VERSION 5.7 ;
  NOWIREEXTENSIONATPIN ON ;
  DIVIDERCHAR "/" ;
  BUSBITCHARS "[]" ;
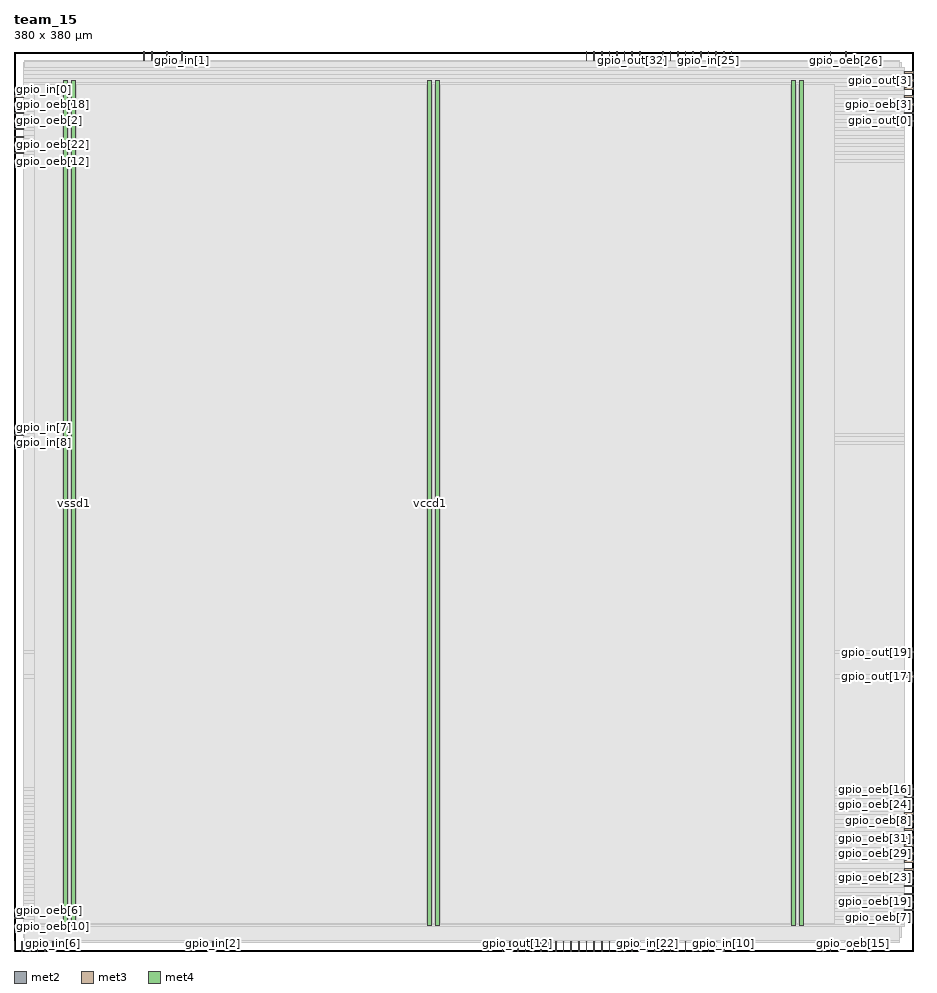
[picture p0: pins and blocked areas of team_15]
MACRO team_15
  CLASS BLOCK ;
  FOREIGN team_15 ;
  ORIGIN 0.000 0.000 ;
  SIZE 380.000 BY 380.000 ;
  PIN clk
    DIRECTION INPUT ;
    USE SIGNAL ;
    PORT
      LAYER met2 ;
        RECT 0.090 0.000 0.370 4.000 ;
    END
  END clk
  PIN en
    DIRECTION INPUT ;
    USE SIGNAL ;
    PORT
      LAYER met2 ;
        RECT 3.310 0.000 3.590 4.000 ;
    END
  END en
  PIN gpio_in[0]
    DIRECTION INPUT ;
    USE SIGNAL ;
    ANTENNAGATEAREA 0.647700 ;
    ANTENNADIFFAREA 0.434700 ;
    PORT
      LAYER met3 ;
        RECT 0.000 360.440 4.000 361.040 ;
    END
  END gpio_in[0]
  PIN gpio_in[10]
    DIRECTION INPUT ;
    USE SIGNAL ;
    ANTENNAGATEAREA 0.647700 ;
    ANTENNADIFFAREA 0.434700 ;
    PORT
      LAYER met2 ;
        RECT 299.550 0.000 299.830 4.000 ;
    END
  END gpio_in[10]
  PIN gpio_in[11]
    DIRECTION INPUT ;
    USE SIGNAL ;
    ANTENNAGATEAREA 0.593700 ;
    ANTENNADIFFAREA 0.434700 ;
    PORT
      LAYER met2 ;
        RECT 296.330 0.000 296.610 4.000 ;
    END
  END gpio_in[11]
  PIN gpio_in[12]
    DIRECTION INPUT ;
    USE SIGNAL ;
    ANTENNAGATEAREA 0.593700 ;
    ANTENNADIFFAREA 0.434700 ;
    PORT
      LAYER met2 ;
        RECT 289.890 0.000 290.170 4.000 ;
    END
  END gpio_in[12]
  PIN gpio_in[13]
    DIRECTION INPUT ;
    USE SIGNAL ;
    ANTENNAGATEAREA 0.647700 ;
    ANTENNADIFFAREA 0.434700 ;
    PORT
      LAYER met2 ;
        RECT 283.450 0.000 283.730 4.000 ;
    END
  END gpio_in[13]
  PIN gpio_in[14]
    DIRECTION INPUT ;
    USE SIGNAL ;
    ANTENNAGATEAREA 0.647700 ;
    ANTENNADIFFAREA 0.434700 ;
    PORT
      LAYER met2 ;
        RECT 286.670 0.000 286.950 4.000 ;
    END
  END gpio_in[14]
  PIN gpio_in[15]
    DIRECTION INPUT ;
    USE SIGNAL ;
    ANTENNAGATEAREA 0.593700 ;
    ANTENNADIFFAREA 0.434700 ;
    PORT
      LAYER met2 ;
        RECT 293.110 0.000 293.390 4.000 ;
    END
  END gpio_in[15]
  PIN gpio_in[16]
    DIRECTION INPUT ;
    USE SIGNAL ;
    ANTENNAGATEAREA 0.593700 ;
    ANTENNADIFFAREA 0.434700 ;
    PORT
      LAYER met2 ;
        RECT 280.230 0.000 280.510 4.000 ;
    END
  END gpio_in[16]
  PIN gpio_in[17]
    DIRECTION INPUT ;
    USE SIGNAL ;
    ANTENNAGATEAREA 0.647700 ;
    ANTENNADIFFAREA 0.434700 ;
    PORT
      LAYER met2 ;
        RECT 273.790 0.000 274.070 4.000 ;
    END
  END gpio_in[17]
  PIN gpio_in[18]
    DIRECTION INPUT ;
    USE SIGNAL ;
    ANTENNAGATEAREA 0.647700 ;
    ANTENNADIFFAREA 0.434700 ;
    PORT
      LAYER met2 ;
        RECT 264.130 0.000 264.410 4.000 ;
    END
  END gpio_in[18]
  PIN gpio_in[19]
    DIRECTION INPUT ;
    USE SIGNAL ;
    ANTENNAGATEAREA 0.647700 ;
    ANTENNADIFFAREA 0.434700 ;
    PORT
      LAYER met2 ;
        RECT 257.690 0.000 257.970 4.000 ;
    END
  END gpio_in[19]
  PIN gpio_in[1]
    DIRECTION INPUT ;
    USE SIGNAL ;
    ANTENNAGATEAREA 0.631200 ;
    ANTENNADIFFAREA 0.434700 ;
    PORT
      LAYER met2 ;
        RECT 70.930 376.000 71.210 380.000 ;
    END
  END gpio_in[1]
  PIN gpio_in[20]
    DIRECTION INPUT ;
    USE SIGNAL ;
    ANTENNAGATEAREA 0.647700 ;
    ANTENNADIFFAREA 0.434700 ;
    PORT
      LAYER met2 ;
        RECT 244.810 0.000 245.090 4.000 ;
    END
  END gpio_in[20]
  PIN gpio_in[21]
    DIRECTION INPUT ;
    USE SIGNAL ;
    ANTENNAGATEAREA 0.647700 ;
    ANTENNADIFFAREA 0.434700 ;
    PORT
      LAYER met2 ;
        RECT 270.570 0.000 270.850 4.000 ;
    END
  END gpio_in[21]
  PIN gpio_in[22]
    DIRECTION INPUT ;
    USE SIGNAL ;
    ANTENNAGATEAREA 0.647700 ;
    ANTENNADIFFAREA 0.434700 ;
    PORT
      LAYER met2 ;
        RECT 267.350 0.000 267.630 4.000 ;
    END
  END gpio_in[22]
  PIN gpio_in[23]
    DIRECTION INPUT ;
    USE SIGNAL ;
    ANTENNAGATEAREA 0.593700 ;
    ANTENNADIFFAREA 0.434700 ;
    PORT
      LAYER met2 ;
        RECT 251.250 0.000 251.530 4.000 ;
    END
  END gpio_in[23]
  PIN gpio_in[24]
    DIRECTION INPUT ;
    USE SIGNAL ;
    ANTENNAGATEAREA 0.647700 ;
    ANTENNADIFFAREA 0.434700 ;
    PORT
      LAYER met2 ;
        RECT 260.910 0.000 261.190 4.000 ;
    END
  END gpio_in[24]
  PIN gpio_in[25]
    DIRECTION INPUT ;
    USE SIGNAL ;
    ANTENNAGATEAREA 0.593700 ;
    ANTENNADIFFAREA 0.434700 ;
    PORT
      LAYER met2 ;
        RECT 293.110 376.000 293.390 380.000 ;
    END
  END gpio_in[25]
  PIN gpio_in[26]
    DIRECTION INPUT ;
    USE SIGNAL ;
    ANTENNAGATEAREA 0.593700 ;
    ANTENNADIFFAREA 0.434700 ;
    PORT
      LAYER met2 ;
        RECT 302.770 376.000 303.050 380.000 ;
    END
  END gpio_in[26]
  PIN gpio_in[27]
    DIRECTION INPUT ;
    USE SIGNAL ;
    ANTENNAGATEAREA 0.593700 ;
    ANTENNADIFFAREA 0.434700 ;
    PORT
      LAYER met2 ;
        RECT 296.330 376.000 296.610 380.000 ;
    END
  END gpio_in[27]
  PIN gpio_in[28]
    DIRECTION INPUT ;
    USE SIGNAL ;
    ANTENNAGATEAREA 0.593700 ;
    ANTENNADIFFAREA 0.434700 ;
    PORT
      LAYER met2 ;
        RECT 283.450 376.000 283.730 380.000 ;
    END
  END gpio_in[28]
  PIN gpio_in[29]
    DIRECTION INPUT ;
    USE SIGNAL ;
    ANTENNAGATEAREA 0.593700 ;
    ANTENNADIFFAREA 0.434700 ;
    PORT
      LAYER met2 ;
        RECT 289.890 376.000 290.170 380.000 ;
    END
  END gpio_in[29]
  PIN gpio_in[2]
    DIRECTION INPUT ;
    USE SIGNAL ;
    ANTENNAGATEAREA 0.631200 ;
    ANTENNADIFFAREA 0.434700 ;
    PORT
      LAYER met2 ;
        RECT 83.810 0.000 84.090 4.000 ;
    END
  END gpio_in[2]
  PIN gpio_in[30]
    DIRECTION INPUT ;
    USE SIGNAL ;
    ANTENNAGATEAREA 0.593700 ;
    ANTENNADIFFAREA 0.434700 ;
    PORT
      LAYER met2 ;
        RECT 286.670 376.000 286.950 380.000 ;
    END
  END gpio_in[30]
  PIN gpio_in[31]
    DIRECTION INPUT ;
    USE SIGNAL ;
    ANTENNAGATEAREA 0.593700 ;
    ANTENNADIFFAREA 0.434700 ;
    PORT
      LAYER met2 ;
        RECT 273.790 376.000 274.070 380.000 ;
    END
  END gpio_in[31]
  PIN gpio_in[32]
    DIRECTION INPUT ;
    USE SIGNAL ;
    ANTENNAGATEAREA 0.593700 ;
    ANTENNADIFFAREA 0.434700 ;
    PORT
      LAYER met2 ;
        RECT 280.230 376.000 280.510 380.000 ;
    END
  END gpio_in[32]
  PIN gpio_in[33]
    DIRECTION INPUT ;
    USE SIGNAL ;
    ANTENNAGATEAREA 0.647700 ;
    ANTENNADIFFAREA 0.434700 ;
    PORT
      LAYER met2 ;
        RECT 299.550 376.000 299.830 380.000 ;
    END
  END gpio_in[33]
  PIN gpio_in[3]
    DIRECTION INPUT ;
    USE SIGNAL ;
    PORT
      LAYER met2 ;
        RECT 6.530 0.000 6.810 4.000 ;
    END
  END gpio_in[3]
  PIN gpio_in[4]
    DIRECTION INPUT ;
    USE SIGNAL ;
    PORT
      LAYER met2 ;
        RECT 9.750 0.000 10.030 4.000 ;
    END
  END gpio_in[4]
  PIN gpio_in[5]
    DIRECTION INPUT ;
    USE SIGNAL ;
    PORT
      LAYER met2 ;
        RECT 12.970 0.000 13.250 4.000 ;
    END
  END gpio_in[5]
  PIN gpio_in[6]
    DIRECTION INPUT ;
    USE SIGNAL ;
    PORT
      LAYER met2 ;
        RECT 16.190 0.000 16.470 4.000 ;
    END
  END gpio_in[6]
  PIN gpio_in[7]
    DIRECTION INPUT ;
    USE SIGNAL ;
    ANTENNAGATEAREA 0.593700 ;
    ANTENNADIFFAREA 0.434700 ;
    PORT
      LAYER met3 ;
        RECT 0.000 217.640 4.000 218.240 ;
    END
  END gpio_in[7]
  PIN gpio_in[8]
    DIRECTION INPUT ;
    USE SIGNAL ;
    ANTENNAGATEAREA 0.682200 ;
    ANTENNADIFFAREA 0.434700 ;
    PORT
      LAYER met3 ;
        RECT 0.000 214.240 4.000 214.840 ;
    END
  END gpio_in[8]
  PIN gpio_in[9]
    DIRECTION INPUT ;
    USE SIGNAL ;
    ANTENNAGATEAREA 0.647700 ;
    ANTENNADIFFAREA 0.434700 ;
    PORT
      LAYER met2 ;
        RECT 277.010 0.000 277.290 4.000 ;
    END
  END gpio_in[9]
  PIN gpio_oeb[0]
    DIRECTION OUTPUT ;
    USE SIGNAL ;
    PORT
      LAYER met3 ;
        RECT 376.000 370.640 380.000 371.240 ;
    END
  END gpio_oeb[0]
  PIN gpio_oeb[10]
    DIRECTION OUTPUT ;
    USE SIGNAL ;
    PORT
      LAYER met3 ;
        RECT 0.000 10.240 4.000 10.840 ;
    END
  END gpio_oeb[10]
  PIN gpio_oeb[11]
    DIRECTION OUTPUT ;
    USE SIGNAL ;
    ANTENNADIFFAREA 0.445500 ;
    PORT
      LAYER met2 ;
        RECT 344.630 0.000 344.910 4.000 ;
    END
  END gpio_oeb[11]
  PIN gpio_oeb[12]
    DIRECTION OUTPUT ;
    USE SIGNAL ;
    PORT
      LAYER met3 ;
        RECT 0.000 333.240 4.000 333.840 ;
    END
  END gpio_oeb[12]
  PIN gpio_oeb[13]
    DIRECTION OUTPUT ;
    USE SIGNAL ;
    ANTENNADIFFAREA 0.445500 ;
    PORT
      LAYER met2 ;
        RECT 351.070 0.000 351.350 4.000 ;
    END
  END gpio_oeb[13]
  PIN gpio_oeb[14]
    DIRECTION OUTPUT ;
    USE SIGNAL ;
    PORT
      LAYER met3 ;
        RECT 376.000 54.440 380.000 55.040 ;
    END
  END gpio_oeb[14]
  PIN gpio_oeb[15]
    DIRECTION OUTPUT ;
    USE SIGNAL ;
    ANTENNADIFFAREA 0.445500 ;
    PORT
      LAYER met2 ;
        RECT 354.290 0.000 354.570 4.000 ;
    END
  END gpio_oeb[15]
  PIN gpio_oeb[16]
    DIRECTION OUTPUT ;
    USE SIGNAL ;
    PORT
      LAYER met3 ;
        RECT 376.000 68.040 380.000 68.640 ;
    END
  END gpio_oeb[16]
  PIN gpio_oeb[17]
    DIRECTION OUTPUT ;
    USE SIGNAL ;
    ANTENNADIFFAREA 0.445500 ;
    PORT
      LAYER met2 ;
        RECT 360.730 0.000 361.010 4.000 ;
    END
  END gpio_oeb[17]
  PIN gpio_oeb[18]
    DIRECTION OUTPUT ;
    USE SIGNAL ;
    PORT
      LAYER met3 ;
        RECT 0.000 357.040 4.000 357.640 ;
    END
  END gpio_oeb[18]
  PIN gpio_oeb[19]
    DIRECTION OUTPUT ;
    USE SIGNAL ;
    ANTENNADIFFAREA 0.445500 ;
    PORT
      LAYER met3 ;
        RECT 376.000 20.440 380.000 21.040 ;
    END
  END gpio_oeb[19]
  PIN gpio_oeb[1]
    DIRECTION OUTPUT ;
    USE SIGNAL ;
    PORT
      LAYER met3 ;
        RECT 0.000 353.640 4.000 354.240 ;
    END
  END gpio_oeb[1]
  PIN gpio_oeb[20]
    DIRECTION OUTPUT ;
    USE SIGNAL ;
    PORT
      LAYER met3 ;
        RECT 0.000 346.840 4.000 347.440 ;
    END
  END gpio_oeb[20]
  PIN gpio_oeb[21]
    DIRECTION OUTPUT ;
    USE SIGNAL ;
    ANTENNADIFFAREA 0.445500 ;
    PORT
      LAYER met3 ;
        RECT 376.000 23.840 380.000 24.440 ;
    END
  END gpio_oeb[21]
  PIN gpio_oeb[22]
    DIRECTION OUTPUT ;
    USE SIGNAL ;
    PORT
      LAYER met3 ;
        RECT 0.000 340.040 4.000 340.640 ;
    END
  END gpio_oeb[22]
  PIN gpio_oeb[23]
    DIRECTION OUTPUT ;
    USE SIGNAL ;
    ANTENNADIFFAREA 0.445500 ;
    PORT
      LAYER met3 ;
        RECT 376.000 30.640 380.000 31.240 ;
    END
  END gpio_oeb[23]
  PIN gpio_oeb[24]
    DIRECTION OUTPUT ;
    USE SIGNAL ;
    PORT
      LAYER met3 ;
        RECT 376.000 64.640 380.000 65.240 ;
    END
  END gpio_oeb[24]
  PIN gpio_oeb[25]
    DIRECTION OUTPUT ;
    USE SIGNAL ;
    ANTENNADIFFAREA 0.445500 ;
    PORT
      LAYER met3 ;
        RECT 376.000 34.040 380.000 34.640 ;
    END
  END gpio_oeb[25]
  PIN gpio_oeb[26]
    DIRECTION OUTPUT ;
    USE SIGNAL ;
    PORT
      LAYER met2 ;
        RECT 351.070 376.000 351.350 380.000 ;
    END
  END gpio_oeb[26]
  PIN gpio_oeb[27]
    DIRECTION OUTPUT ;
    USE SIGNAL ;
    ANTENNADIFFAREA 0.445500 ;
    PORT
      LAYER met3 ;
        RECT 376.000 37.440 380.000 38.040 ;
    END
  END gpio_oeb[27]
  PIN gpio_oeb[28]
    DIRECTION OUTPUT ;
    USE SIGNAL ;
    PORT
      LAYER met3 ;
        RECT 376.000 360.440 380.000 361.040 ;
    END
  END gpio_oeb[28]
  PIN gpio_oeb[29]
    DIRECTION OUTPUT ;
    USE SIGNAL ;
    ANTENNADIFFAREA 0.445500 ;
    PORT
      LAYER met3 ;
        RECT 376.000 40.840 380.000 41.440 ;
    END
  END gpio_oeb[29]
  PIN gpio_oeb[2]
    DIRECTION OUTPUT ;
    USE SIGNAL ;
    PORT
      LAYER met3 ;
        RECT 0.000 350.240 4.000 350.840 ;
    END
  END gpio_oeb[2]
  PIN gpio_oeb[30]
    DIRECTION OUTPUT ;
    USE SIGNAL ;
    PORT
      LAYER met3 ;
        RECT 376.000 27.240 380.000 27.840 ;
    END
  END gpio_oeb[30]
  PIN gpio_oeb[31]
    DIRECTION OUTPUT ;
    USE SIGNAL ;
    ANTENNADIFFAREA 0.445500 ;
    PORT
      LAYER met3 ;
        RECT 376.000 44.240 380.000 44.840 ;
    END
  END gpio_oeb[31]
  PIN gpio_oeb[32]
    DIRECTION OUTPUT ;
    USE SIGNAL ;
    PORT
      LAYER met3 ;
        RECT 0.000 17.040 4.000 17.640 ;
    END
  END gpio_oeb[32]
  PIN gpio_oeb[33]
    DIRECTION OUTPUT ;
    USE SIGNAL ;
    ANTENNADIFFAREA 0.445500 ;
    PORT
      LAYER met3 ;
        RECT 376.000 47.640 380.000 48.240 ;
    END
  END gpio_oeb[33]
  PIN gpio_oeb[3]
    DIRECTION OUTPUT ;
    USE SIGNAL ;
    PORT
      LAYER met3 ;
        RECT 376.000 357.040 380.000 357.640 ;
    END
  END gpio_oeb[3]
  PIN gpio_oeb[4]
    DIRECTION OUTPUT ;
    USE SIGNAL ;
    PORT
      LAYER met3 ;
        RECT 0.000 343.440 4.000 344.040 ;
    END
  END gpio_oeb[4]
  PIN gpio_oeb[5]
    DIRECTION OUTPUT ;
    USE SIGNAL ;
    PORT
      LAYER met3 ;
        RECT 376.000 353.640 380.000 354.240 ;
    END
  END gpio_oeb[5]
  PIN gpio_oeb[6]
    DIRECTION OUTPUT ;
    USE SIGNAL ;
    PORT
      LAYER met3 ;
        RECT 0.000 13.640 4.000 14.240 ;
    END
  END gpio_oeb[6]
  PIN gpio_oeb[7]
    DIRECTION OUTPUT ;
    USE SIGNAL ;
    PORT
      LAYER met3 ;
        RECT 376.000 17.040 380.000 17.640 ;
    END
  END gpio_oeb[7]
  PIN gpio_oeb[8]
    DIRECTION OUTPUT ;
    USE SIGNAL ;
    PORT
      LAYER met3 ;
        RECT 376.000 57.840 380.000 58.440 ;
    END
  END gpio_oeb[8]
  PIN gpio_oeb[9]
    DIRECTION OUTPUT ;
    USE SIGNAL ;
    ANTENNADIFFAREA 0.445500 ;
    PORT
      LAYER met2 ;
        RECT 341.410 0.000 341.690 4.000 ;
    END
  END gpio_oeb[9]
  PIN gpio_out[0]
    DIRECTION OUTPUT ;
    USE SIGNAL ;
    PORT
      LAYER met3 ;
        RECT 376.000 350.240 380.000 350.840 ;
    END
  END gpio_out[0]
  PIN gpio_out[10]
    DIRECTION OUTPUT ;
    USE SIGNAL ;
    ANTENNADIFFAREA 0.445500 ;
    PORT
      LAYER met2 ;
        RECT 206.170 0.000 206.450 4.000 ;
    END
  END gpio_out[10]
  PIN gpio_out[11]
    DIRECTION OUTPUT ;
    USE SIGNAL ;
    ANTENNADIFFAREA 0.445500 ;
    PORT
      LAYER met2 ;
        RECT 209.390 0.000 209.670 4.000 ;
    END
  END gpio_out[11]
  PIN gpio_out[12]
    DIRECTION OUTPUT ;
    USE SIGNAL ;
    ANTENNADIFFAREA 0.445500 ;
    PORT
      LAYER met2 ;
        RECT 212.610 0.000 212.890 4.000 ;
    END
  END gpio_out[12]
  PIN gpio_out[13]
    DIRECTION OUTPUT ;
    USE SIGNAL ;
    ANTENNADIFFAREA 0.445500 ;
    PORT
      LAYER met2 ;
        RECT 228.710 0.000 228.990 4.000 ;
    END
  END gpio_out[13]
  PIN gpio_out[14]
    DIRECTION OUTPUT ;
    USE SIGNAL ;
    ANTENNADIFFAREA 0.445500 ;
    PORT
      LAYER met2 ;
        RECT 225.490 0.000 225.770 4.000 ;
    END
  END gpio_out[14]
  PIN gpio_out[15]
    DIRECTION OUTPUT ;
    USE SIGNAL ;
    ANTENNADIFFAREA 0.445500 ;
    PORT
      LAYER met2 ;
        RECT 219.050 0.000 219.330 4.000 ;
    END
  END gpio_out[15]
  PIN gpio_out[16]
    DIRECTION OUTPUT ;
    USE SIGNAL ;
    ANTENNADIFFAREA 0.445500 ;
    PORT
      LAYER met2 ;
        RECT 215.830 0.000 216.110 4.000 ;
    END
  END gpio_out[16]
  PIN gpio_out[17]
    DIRECTION OUTPUT ;
    USE SIGNAL ;
    ANTENNADIFFAREA 0.445500 ;
    PORT
      LAYER met3 ;
        RECT 376.000 115.640 380.000 116.240 ;
    END
  END gpio_out[17]
  PIN gpio_out[18]
    DIRECTION OUTPUT ;
    USE SIGNAL ;
    ANTENNADIFFAREA 0.445500 ;
    PORT
      LAYER met2 ;
        RECT 254.470 0.000 254.750 4.000 ;
    END
  END gpio_out[18]
  PIN gpio_out[19]
    DIRECTION OUTPUT ;
    USE SIGNAL ;
    ANTENNADIFFAREA 0.445500 ;
    PORT
      LAYER met3 ;
        RECT 376.000 125.840 380.000 126.440 ;
    END
  END gpio_out[19]
  PIN gpio_out[1]
    DIRECTION OUTPUT ;
    USE SIGNAL ;
    PORT
      LAYER met3 ;
        RECT 0.000 336.640 4.000 337.240 ;
    END
  END gpio_out[1]
  PIN gpio_out[20]
    DIRECTION OUTPUT ;
    USE SIGNAL ;
    ANTENNADIFFAREA 0.445500 ;
    PORT
      LAYER met2 ;
        RECT 222.270 0.000 222.550 4.000 ;
    END
  END gpio_out[20]
  PIN gpio_out[21]
    DIRECTION OUTPUT ;
    USE SIGNAL ;
    ANTENNADIFFAREA 0.445500 ;
    PORT
      LAYER met2 ;
        RECT 235.150 0.000 235.430 4.000 ;
    END
  END gpio_out[21]
  PIN gpio_out[22]
    DIRECTION OUTPUT ;
    USE SIGNAL ;
    ANTENNADIFFAREA 0.445500 ;
    PORT
      LAYER met2 ;
        RECT 238.370 0.000 238.650 4.000 ;
    END
  END gpio_out[22]
  PIN gpio_out[23]
    DIRECTION OUTPUT ;
    USE SIGNAL ;
    ANTENNADIFFAREA 0.445500 ;
    PORT
      LAYER met2 ;
        RECT 231.930 0.000 232.210 4.000 ;
    END
  END gpio_out[23]
  PIN gpio_out[24]
    DIRECTION OUTPUT ;
    USE SIGNAL ;
    ANTENNADIFFAREA 0.445500 ;
    PORT
      LAYER met2 ;
        RECT 241.590 0.000 241.870 4.000 ;
    END
  END gpio_out[24]
  PIN gpio_out[25]
    DIRECTION OUTPUT ;
    USE SIGNAL ;
    ANTENNADIFFAREA 0.445500 ;
    PORT
      LAYER met2 ;
        RECT 264.130 376.000 264.410 380.000 ;
    END
  END gpio_out[25]
  PIN gpio_out[26]
    DIRECTION OUTPUT ;
    USE SIGNAL ;
    ANTENNADIFFAREA 0.445500 ;
    PORT
      LAYER met2 ;
        RECT 254.470 376.000 254.750 380.000 ;
    END
  END gpio_out[26]
  PIN gpio_out[27]
    DIRECTION OUTPUT ;
    USE SIGNAL ;
    ANTENNADIFFAREA 0.445500 ;
    PORT
      LAYER met2 ;
        RECT 244.810 376.000 245.090 380.000 ;
    END
  END gpio_out[27]
  PIN gpio_out[28]
    DIRECTION OUTPUT ;
    USE SIGNAL ;
    ANTENNADIFFAREA 0.445500 ;
    PORT
      LAYER met2 ;
        RECT 257.690 376.000 257.970 380.000 ;
    END
  END gpio_out[28]
  PIN gpio_out[29]
    DIRECTION OUTPUT ;
    USE SIGNAL ;
    ANTENNADIFFAREA 0.445500 ;
    PORT
      LAYER met2 ;
        RECT 248.030 376.000 248.310 380.000 ;
    END
  END gpio_out[29]
  PIN gpio_out[2]
    DIRECTION OUTPUT ;
    USE SIGNAL ;
    PORT
      LAYER met3 ;
        RECT 376.000 61.240 380.000 61.840 ;
    END
  END gpio_out[2]
  PIN gpio_out[30]
    DIRECTION OUTPUT ;
    USE SIGNAL ;
    ANTENNADIFFAREA 0.445500 ;
    PORT
      LAYER met2 ;
        RECT 251.250 376.000 251.530 380.000 ;
    END
  END gpio_out[30]
  PIN gpio_out[31]
    DIRECTION OUTPUT ;
    USE SIGNAL ;
    ANTENNADIFFAREA 0.445500 ;
    PORT
      LAYER met2 ;
        RECT 241.590 376.000 241.870 380.000 ;
    END
  END gpio_out[31]
  PIN gpio_out[32]
    DIRECTION OUTPUT ;
    USE SIGNAL ;
    ANTENNADIFFAREA 0.445500 ;
    PORT
      LAYER met2 ;
        RECT 260.910 376.000 261.190 380.000 ;
    END
  END gpio_out[32]
  PIN gpio_out[33]
    DIRECTION OUTPUT ;
    USE SIGNAL ;
    ANTENNADIFFAREA 0.445500 ;
    PORT
      LAYER met2 ;
        RECT 277.010 376.000 277.290 380.000 ;
    END
  END gpio_out[33]
  PIN gpio_out[3]
    DIRECTION OUTPUT ;
    USE SIGNAL ;
    PORT
      LAYER met3 ;
        RECT 376.000 367.240 380.000 367.840 ;
    END
  END gpio_out[3]
  PIN gpio_out[4]
    DIRECTION OUTPUT ;
    USE SIGNAL ;
    ANTENNADIFFAREA 0.445500 ;
    PORT
      LAYER met2 ;
        RECT 64.490 376.000 64.770 380.000 ;
    END
  END gpio_out[4]
  PIN gpio_out[5]
    DIRECTION OUTPUT ;
    USE SIGNAL ;
    ANTENNADIFFAREA 0.445500 ;
    PORT
      LAYER met2 ;
        RECT 58.050 376.000 58.330 380.000 ;
    END
  END gpio_out[5]
  PIN gpio_out[6]
    DIRECTION OUTPUT ;
    USE SIGNAL ;
    ANTENNADIFFAREA 0.445500 ;
    PORT
      LAYER met2 ;
        RECT 54.830 376.000 55.110 380.000 ;
    END
  END gpio_out[6]
  PIN gpio_out[7]
    DIRECTION OUTPUT ;
    USE SIGNAL ;
    PORT
      LAYER met2 ;
        RECT 344.630 376.000 344.910 380.000 ;
    END
  END gpio_out[7]
  PIN gpio_out[8]
    DIRECTION OUTPUT ;
    USE SIGNAL ;
    PORT
      LAYER met3 ;
        RECT 376.000 363.840 380.000 364.440 ;
    END
  END gpio_out[8]
  PIN gpio_out[9]
    DIRECTION OUTPUT ;
    USE SIGNAL ;
    ANTENNADIFFAREA 0.445500 ;
    PORT
      LAYER met2 ;
        RECT 248.030 0.000 248.310 4.000 ;
    END
  END gpio_out[9]
  PIN nrst
    DIRECTION INPUT ;
    USE SIGNAL ;
    ANTENNAGATEAREA 0.647700 ;
    ANTENNADIFFAREA 0.434700 ;
    PORT
      LAYER met3 ;
        RECT 376.000 51.040 380.000 51.640 ;
    END
  END nrst
  PIN vccd1
    DIRECTION INOUT ;
    USE POWER ;
    PORT
      LAYER met4 ;
        RECT 21.040 10.640 22.640 367.440 ;
    END
    PORT
      LAYER met4 ;
        RECT 174.640 10.640 176.240 367.440 ;
    END
    PORT
      LAYER met4 ;
        RECT 328.240 10.640 329.840 367.440 ;
    END
  END vccd1
  PIN vssd1
    DIRECTION INOUT ;
    USE GROUND ;
    PORT
      LAYER met4 ;
        RECT 24.340 10.640 25.940 367.440 ;
    END
    PORT
      LAYER met4 ;
        RECT 177.940 10.640 179.540 367.440 ;
    END
    PORT
      LAYER met4 ;
        RECT 331.540 10.640 333.140 367.440 ;
    END
  END vssd1
  OBS
      LAYER nwell ;
        RECT 5.330 10.760 374.630 367.390 ;
      LAYER li1 ;
        RECT 5.520 10.795 374.440 367.285 ;
      LAYER met1 ;
        RECT 4.210 5.820 374.740 374.980 ;
      LAYER met2 ;
        RECT 4.230 375.720 54.550 376.000 ;
        RECT 55.390 375.720 57.770 376.000 ;
        RECT 58.610 375.720 64.210 376.000 ;
        RECT 65.050 375.720 70.650 376.000 ;
        RECT 71.490 375.720 241.310 376.000 ;
        RECT 242.150 375.720 244.530 376.000 ;
        RECT 245.370 375.720 247.750 376.000 ;
        RECT 248.590 375.720 250.970 376.000 ;
        RECT 251.810 375.720 254.190 376.000 ;
        RECT 255.030 375.720 257.410 376.000 ;
        RECT 258.250 375.720 260.630 376.000 ;
        RECT 261.470 375.720 263.850 376.000 ;
        RECT 264.690 375.720 273.510 376.000 ;
        RECT 274.350 375.720 276.730 376.000 ;
        RECT 277.570 375.720 279.950 376.000 ;
        RECT 280.790 375.720 283.170 376.000 ;
        RECT 284.010 375.720 286.390 376.000 ;
        RECT 287.230 375.720 289.610 376.000 ;
        RECT 290.450 375.720 292.830 376.000 ;
        RECT 293.670 375.720 296.050 376.000 ;
        RECT 296.890 375.720 299.270 376.000 ;
        RECT 300.110 375.720 302.490 376.000 ;
        RECT 303.330 375.720 344.350 376.000 ;
        RECT 345.190 375.720 350.790 376.000 ;
        RECT 351.630 375.720 373.890 376.000 ;
        RECT 4.230 4.280 373.890 375.720 ;
        RECT 4.230 3.670 6.250 4.280 ;
        RECT 7.090 3.670 9.470 4.280 ;
        RECT 10.310 3.670 12.690 4.280 ;
        RECT 13.530 3.670 15.910 4.280 ;
        RECT 16.750 3.670 83.530 4.280 ;
        RECT 84.370 3.670 205.890 4.280 ;
        RECT 206.730 3.670 209.110 4.280 ;
        RECT 209.950 3.670 212.330 4.280 ;
        RECT 213.170 3.670 215.550 4.280 ;
        RECT 216.390 3.670 218.770 4.280 ;
        RECT 219.610 3.670 221.990 4.280 ;
        RECT 222.830 3.670 225.210 4.280 ;
        RECT 226.050 3.670 228.430 4.280 ;
        RECT 229.270 3.670 231.650 4.280 ;
        RECT 232.490 3.670 234.870 4.280 ;
        RECT 235.710 3.670 238.090 4.280 ;
        RECT 238.930 3.670 241.310 4.280 ;
        RECT 242.150 3.670 244.530 4.280 ;
        RECT 245.370 3.670 247.750 4.280 ;
        RECT 248.590 3.670 250.970 4.280 ;
        RECT 251.810 3.670 254.190 4.280 ;
        RECT 255.030 3.670 257.410 4.280 ;
        RECT 258.250 3.670 260.630 4.280 ;
        RECT 261.470 3.670 263.850 4.280 ;
        RECT 264.690 3.670 267.070 4.280 ;
        RECT 267.910 3.670 270.290 4.280 ;
        RECT 271.130 3.670 273.510 4.280 ;
        RECT 274.350 3.670 276.730 4.280 ;
        RECT 277.570 3.670 279.950 4.280 ;
        RECT 280.790 3.670 283.170 4.280 ;
        RECT 284.010 3.670 286.390 4.280 ;
        RECT 287.230 3.670 289.610 4.280 ;
        RECT 290.450 3.670 292.830 4.280 ;
        RECT 293.670 3.670 296.050 4.280 ;
        RECT 296.890 3.670 299.270 4.280 ;
        RECT 300.110 3.670 341.130 4.280 ;
        RECT 341.970 3.670 344.350 4.280 ;
        RECT 345.190 3.670 350.790 4.280 ;
        RECT 351.630 3.670 354.010 4.280 ;
        RECT 354.850 3.670 360.450 4.280 ;
        RECT 361.290 3.670 373.890 4.280 ;
      LAYER met3 ;
        RECT 3.990 371.640 376.000 373.145 ;
        RECT 3.990 370.240 375.600 371.640 ;
        RECT 3.990 368.240 376.000 370.240 ;
        RECT 3.990 366.840 375.600 368.240 ;
        RECT 3.990 364.840 376.000 366.840 ;
        RECT 3.990 363.440 375.600 364.840 ;
        RECT 3.990 361.440 376.000 363.440 ;
        RECT 4.400 360.040 375.600 361.440 ;
        RECT 3.990 358.040 376.000 360.040 ;
        RECT 4.400 356.640 375.600 358.040 ;
        RECT 3.990 354.640 376.000 356.640 ;
        RECT 4.400 353.240 375.600 354.640 ;
        RECT 3.990 351.240 376.000 353.240 ;
        RECT 4.400 349.840 375.600 351.240 ;
        RECT 3.990 347.840 376.000 349.840 ;
        RECT 4.400 346.440 376.000 347.840 ;
        RECT 3.990 344.440 376.000 346.440 ;
        RECT 4.400 343.040 376.000 344.440 ;
        RECT 3.990 341.040 376.000 343.040 ;
        RECT 4.400 339.640 376.000 341.040 ;
        RECT 3.990 337.640 376.000 339.640 ;
        RECT 4.400 336.240 376.000 337.640 ;
        RECT 3.990 334.240 376.000 336.240 ;
        RECT 4.400 332.840 376.000 334.240 ;
        RECT 3.990 218.640 376.000 332.840 ;
        RECT 4.400 217.240 376.000 218.640 ;
        RECT 3.990 215.240 376.000 217.240 ;
        RECT 4.400 213.840 376.000 215.240 ;
        RECT 3.990 126.840 376.000 213.840 ;
        RECT 3.990 125.440 375.600 126.840 ;
        RECT 3.990 116.640 376.000 125.440 ;
        RECT 3.990 115.240 375.600 116.640 ;
        RECT 3.990 69.040 376.000 115.240 ;
        RECT 3.990 67.640 375.600 69.040 ;
        RECT 3.990 65.640 376.000 67.640 ;
        RECT 3.990 64.240 375.600 65.640 ;
        RECT 3.990 62.240 376.000 64.240 ;
        RECT 3.990 60.840 375.600 62.240 ;
        RECT 3.990 58.840 376.000 60.840 ;
        RECT 3.990 57.440 375.600 58.840 ;
        RECT 3.990 55.440 376.000 57.440 ;
        RECT 3.990 54.040 375.600 55.440 ;
        RECT 3.990 52.040 376.000 54.040 ;
        RECT 3.990 50.640 375.600 52.040 ;
        RECT 3.990 48.640 376.000 50.640 ;
        RECT 3.990 47.240 375.600 48.640 ;
        RECT 3.990 45.240 376.000 47.240 ;
        RECT 3.990 43.840 375.600 45.240 ;
        RECT 3.990 41.840 376.000 43.840 ;
        RECT 3.990 40.440 375.600 41.840 ;
        RECT 3.990 38.440 376.000 40.440 ;
        RECT 3.990 37.040 375.600 38.440 ;
        RECT 3.990 35.040 376.000 37.040 ;
        RECT 3.990 33.640 375.600 35.040 ;
        RECT 3.990 31.640 376.000 33.640 ;
        RECT 3.990 30.240 375.600 31.640 ;
        RECT 3.990 28.240 376.000 30.240 ;
        RECT 3.990 26.840 375.600 28.240 ;
        RECT 3.990 24.840 376.000 26.840 ;
        RECT 3.990 23.440 375.600 24.840 ;
        RECT 3.990 21.440 376.000 23.440 ;
        RECT 3.990 20.040 375.600 21.440 ;
        RECT 3.990 18.040 376.000 20.040 ;
        RECT 4.400 16.640 375.600 18.040 ;
        RECT 3.990 14.640 376.000 16.640 ;
        RECT 4.400 13.240 376.000 14.640 ;
        RECT 3.990 11.240 376.000 13.240 ;
        RECT 4.400 10.390 376.000 11.240 ;
      LAYER met4 ;
        RECT 8.575 11.735 20.640 365.665 ;
        RECT 23.040 11.735 23.940 365.665 ;
        RECT 26.340 11.735 174.240 365.665 ;
        RECT 176.640 11.735 177.540 365.665 ;
        RECT 179.940 11.735 327.840 365.665 ;
        RECT 330.240 11.735 331.140 365.665 ;
        RECT 333.540 11.735 346.545 365.665 ;
  END
END team_15
END LIBRARY

